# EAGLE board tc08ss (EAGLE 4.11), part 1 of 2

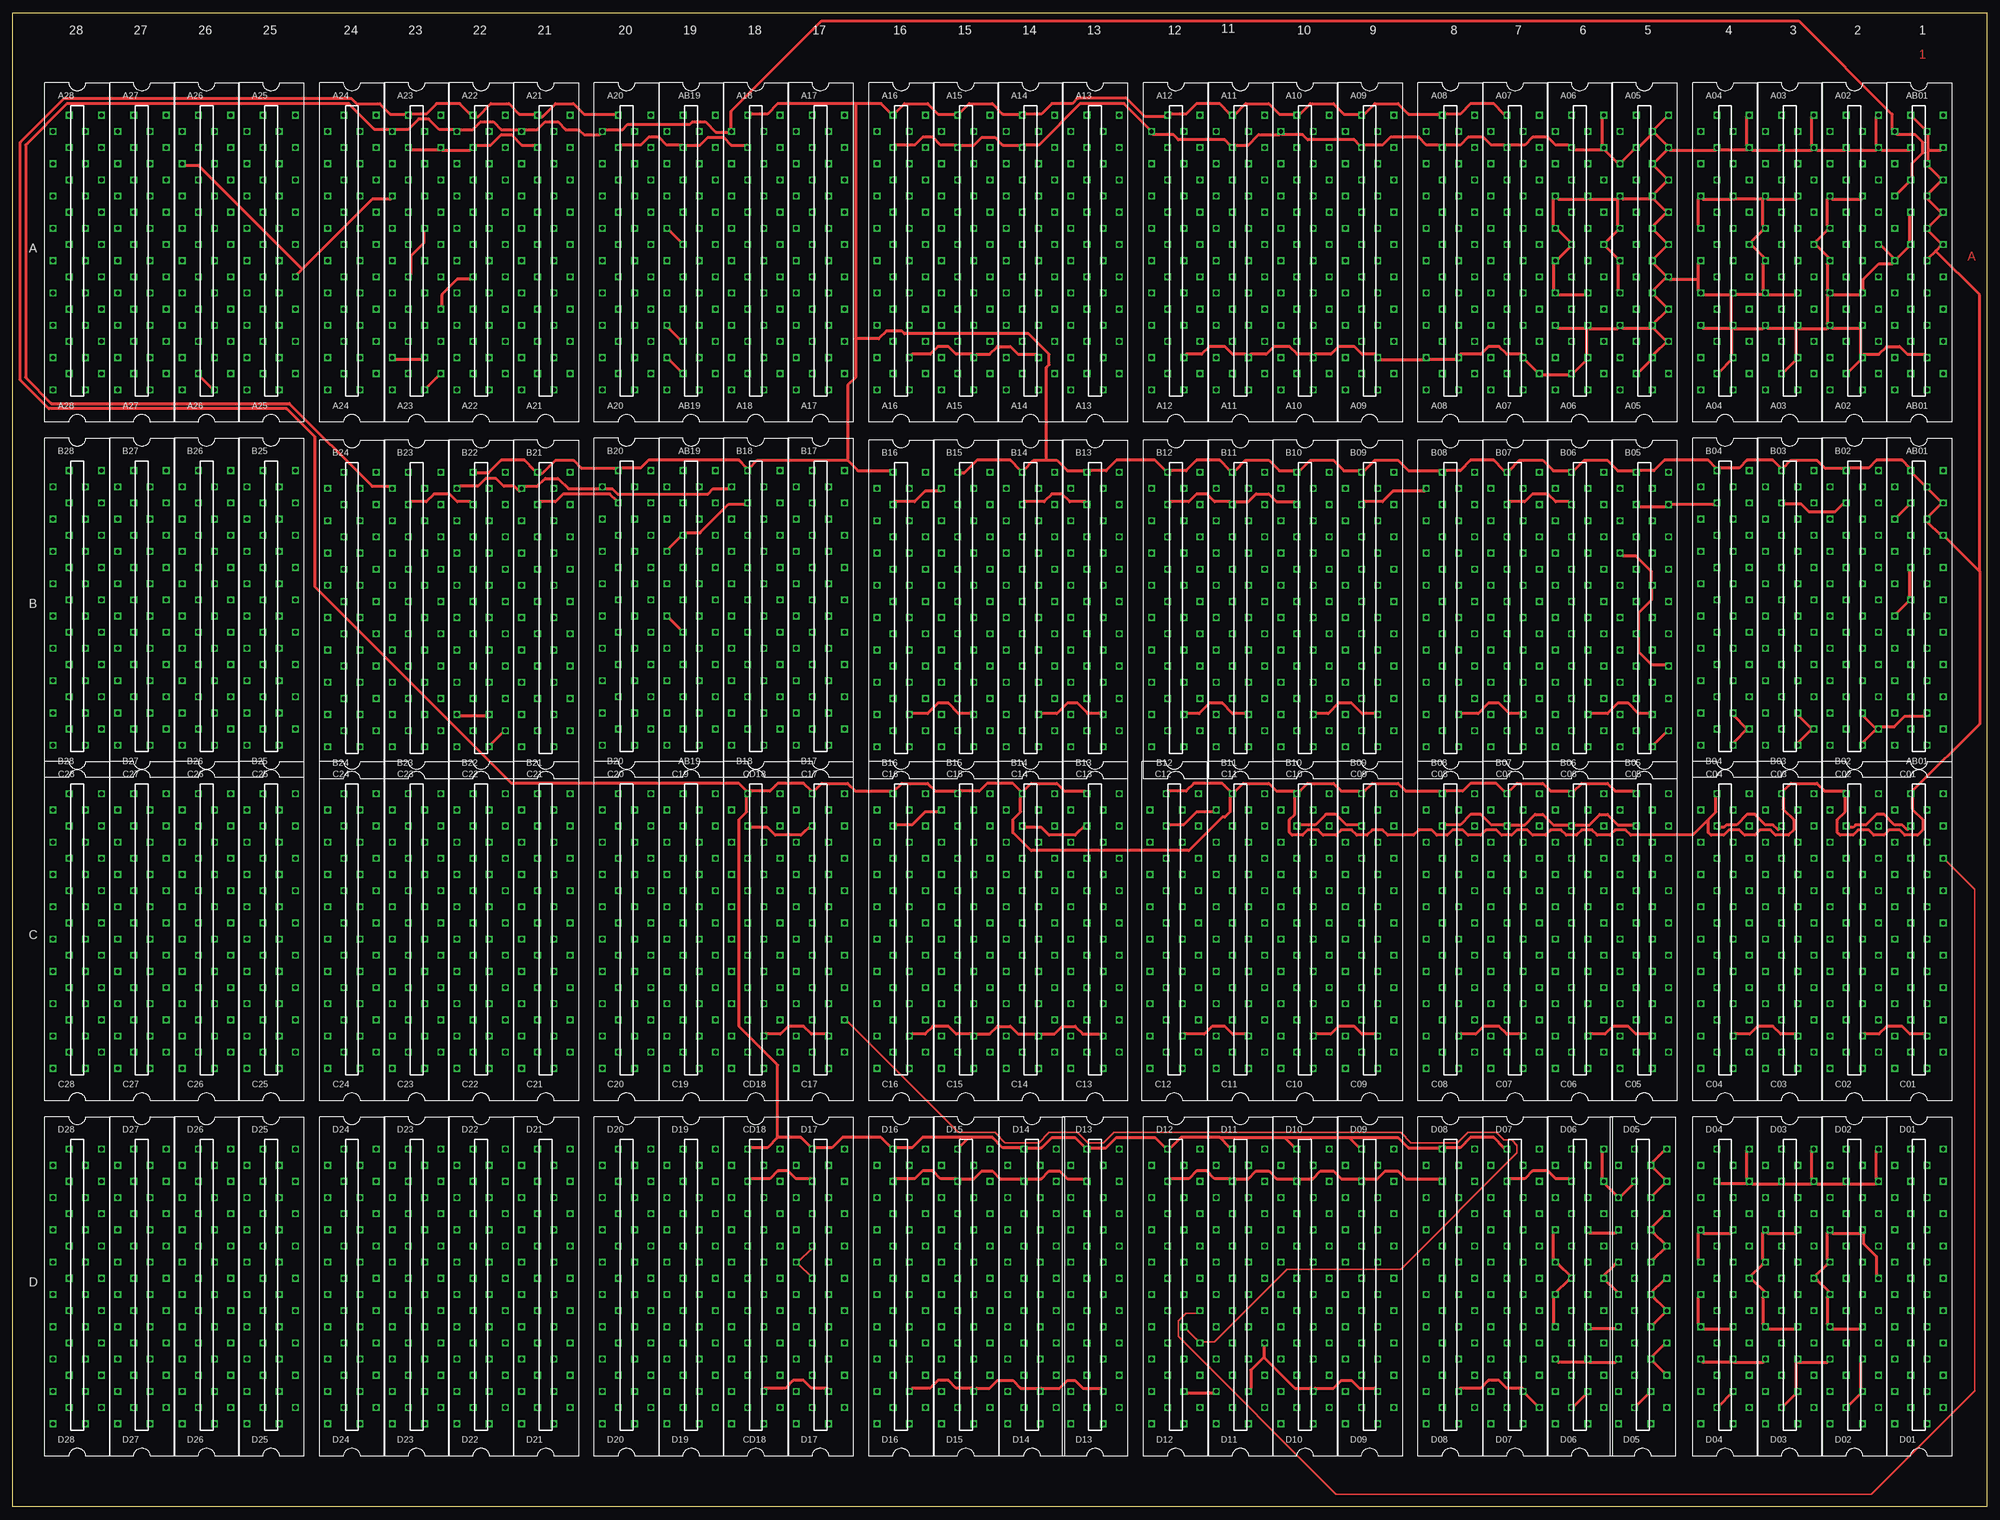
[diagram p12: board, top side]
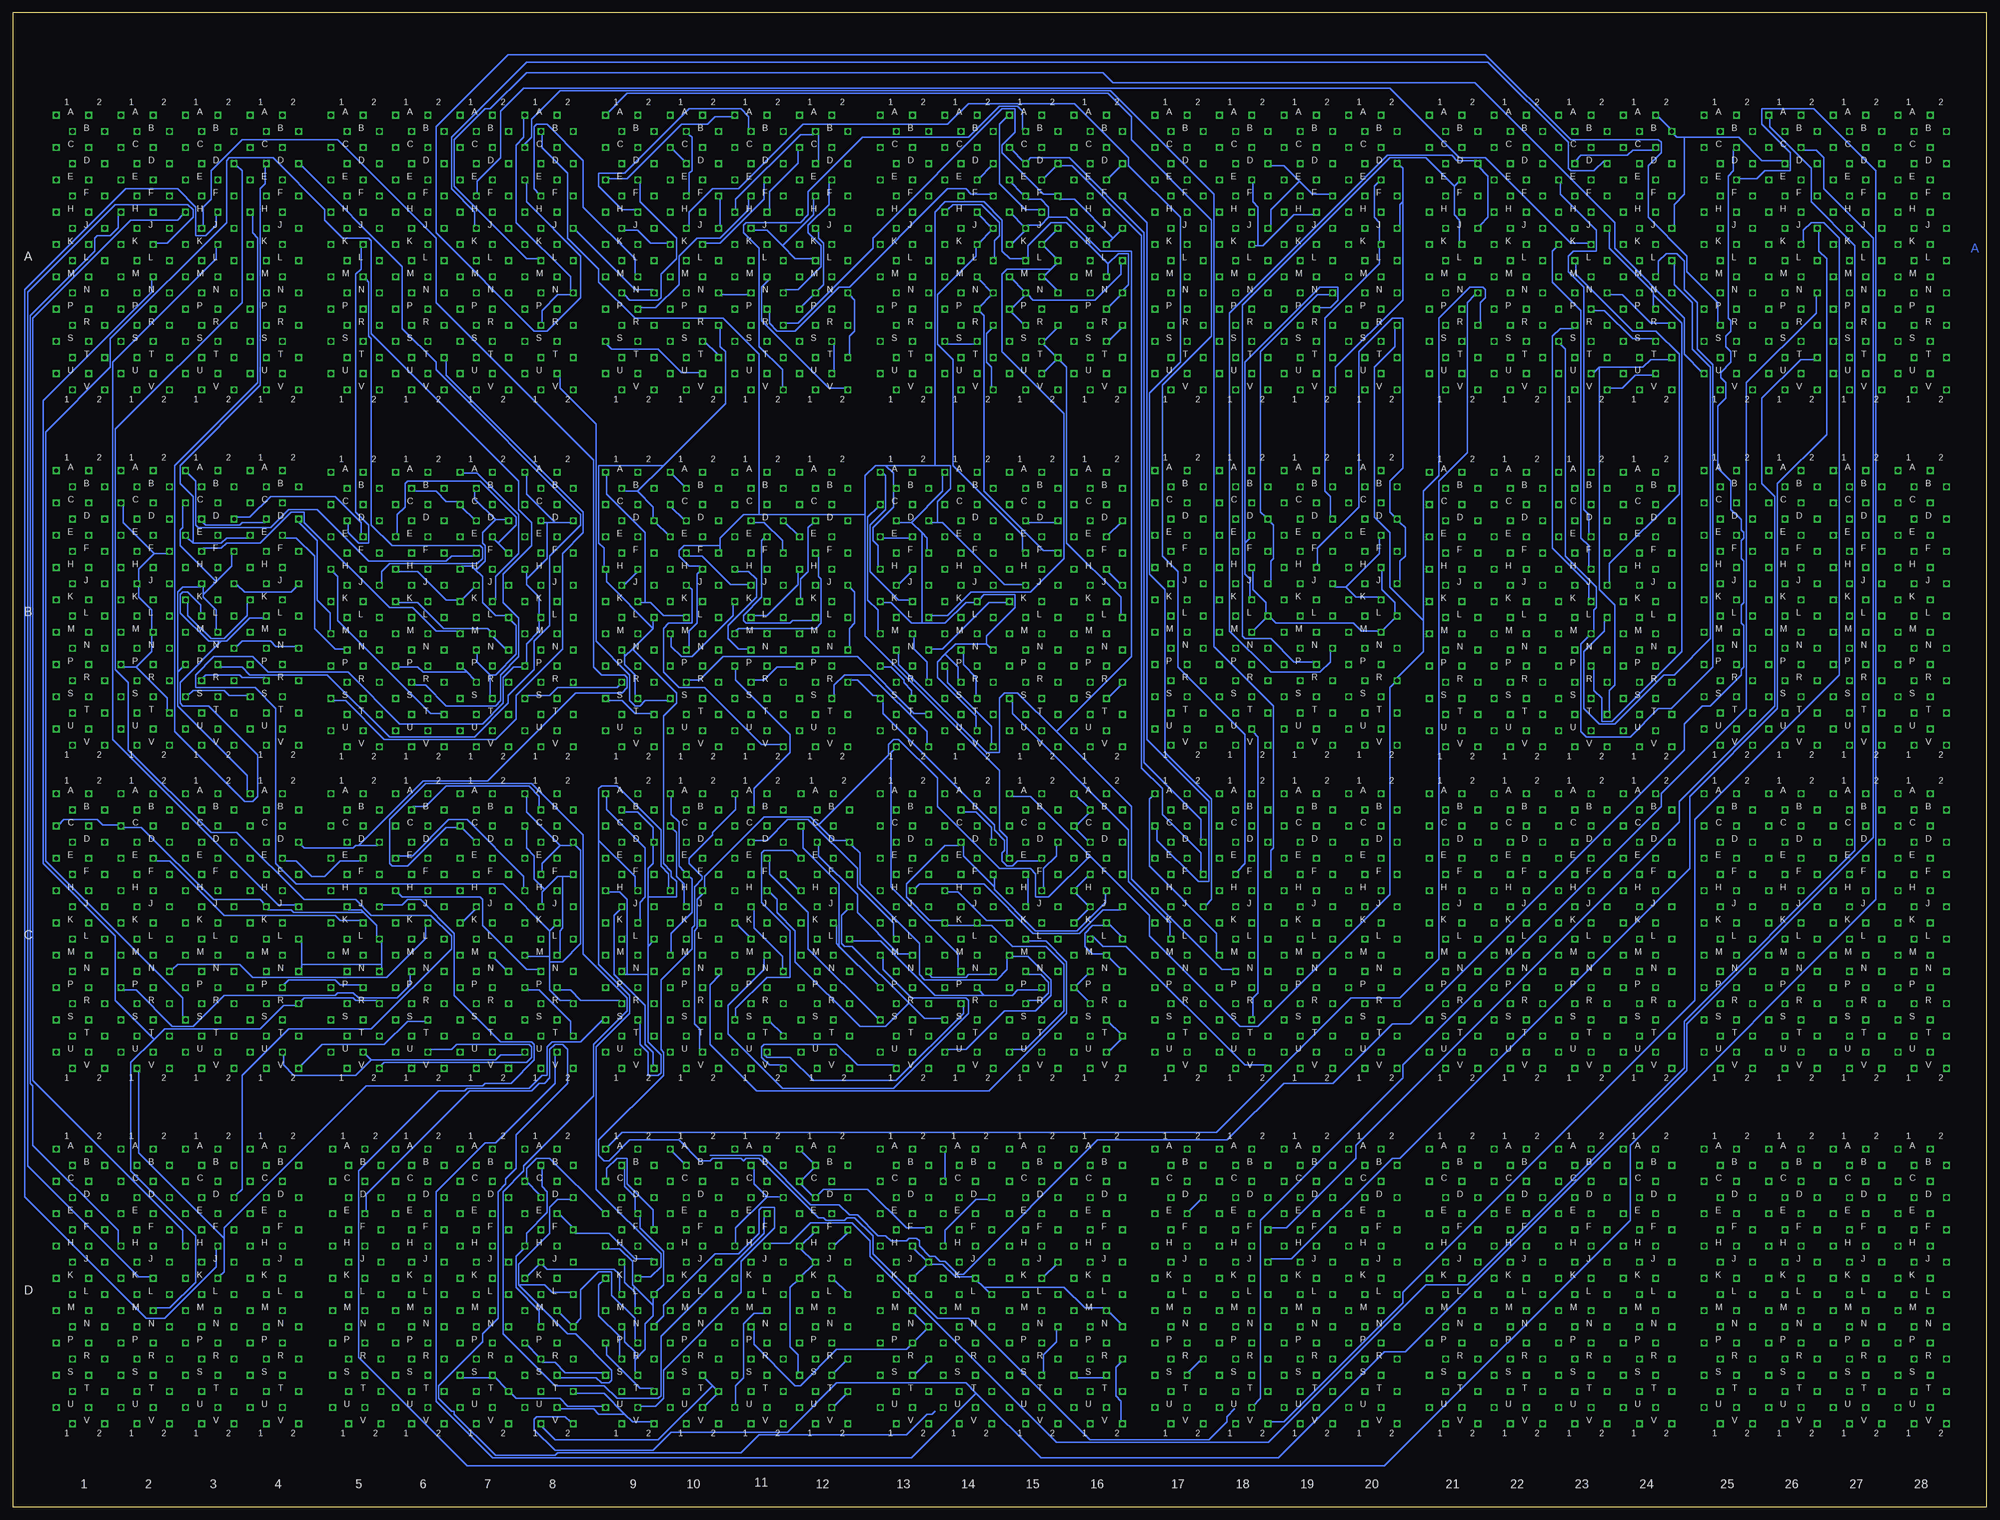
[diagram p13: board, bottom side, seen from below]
Size 387.97 x 293.68 mm. Coordinates in mm from the lower left corner, seen from the top.
Outline: 387.97,0 0,0 0,293.68 387.97,293.68 387.97,0
Copper layers (1*16): Top 0.035mm / dielectric 1.5mm / Bottom 0.035mm
Design rules "10mils": minimum track width 10mil, minimum drill 24mil, track to track 10mil, track to pad 10mil, pad to pad 10mil, via to via 10mil, smd to smd 10mil, copper to edge 40mil, drill to drill 10mil, minimum pad ring 10mil, minimum via ring 8mil, stop-mask expansion 0mil, vias tented up to drill 0mil, thermal gap 10mil
Net classes: 1 Power: width 0.635 mm, drill 0.381 mm, clearance 0.381 mm

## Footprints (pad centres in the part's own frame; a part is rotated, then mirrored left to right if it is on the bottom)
H807 = drill 0.813 square: A1 4.763,28.575; A2 -1.587,28.575; B1 1.587,25.4; B2 -4.763,25.4; C1 4.763,22.225; C2 -1.587,22.225; D1 1.587,19.05; D2 -4.763,19.05; E1 4.763,15.875; E2 -1.587,15.875; F1 1.587,12.7; F2 -4.763,12.7; H1 4.763,9.525; H2 -1.587,9.525; J1 1.587,6.35; J2 -4.763,6.35; K1 4.763,3.175; K2 -1.587,3.175; L1 1.587,0; L2 -4.763,0; M1 4.763,-3.175; M2 -1.587,-3.175; N1 1.587,-6.35; N2 -4.763,-6.35; P1 4.763,-9.525; P2 -1.587,-9.525; R1 1.587,-12.7; R2 -4.763,-12.7; S1 4.763,-15.875; S2 -1.587,-15.875; T1 1.587,-19.05; T2 -4.763,-19.05; U1 4.763,-22.225; U2 -1.587,-22.225; V1 1.587,-25.4; V2 -4.763,-25.4
H807-2 = drill 0.813 square: AA1 4.763,60.325; AA2 -1.587,60.325; AB1 1.587,57.15; AB2 -4.763,57.15; AC1 4.763,53.975; AC2 -1.587,53.975; AD1 1.587,50.8; AD2 -4.763,50.8; AE1 4.763,47.625; AE2 -1.587,47.625; AF1 1.587,44.45; AF2 -4.763,44.45; AH1 4.763,41.275; AH2 -1.587,41.275; AJ1 1.587,38.1; AJ2 -4.763,38.1; AK1 4.763,34.925; AK2 -1.587,34.925; AL1 1.587,31.75; AL2 -4.763,31.75; AM1 4.763,28.575; AM2 -1.587,28.575; AN1 1.587,25.4; AN2 -4.763,25.4; AP1 4.763,22.225; AP2 -1.587,22.225; AR1 1.587,19.05; AR2 -4.763,19.05; AS1 4.763,15.875; AS2 -1.587,15.875; AT1 1.587,12.7; AT2 -4.763,12.7; AU1 4.763,9.525; AU2 -1.587,9.525; AV1 1.587,6.35; AV2 -4.763,6.35; BA1 4.763,-9.525; BA2 -1.587,-9.525; BB1 1.587,-12.7; BB2 -4.763,-12.7; BC1 4.763,-15.875; BC2 -1.587,-15.875; BD1 1.587,-19.05; BD2 -4.763,-19.05; BE1 4.763,-22.225; BE2 -1.587,-22.225; BF1 1.587,-25.4; BF2 -4.763,-25.4; BH1 4.763,-28.575; BH2 -1.587,-28.575; BJ1 1.587,-31.75; BJ2 -4.763,-31.75; BK1 4.763,-34.925; BK2 -1.587,-34.925; BL1 1.587,-38.1; BL2 -4.763,-38.1; BM1 4.763,-41.275; BM2 -1.587,-41.275; BN1 1.587,-44.45; BN2 -4.763,-44.45; BP1 4.763,-47.625; BP2 -1.587,-47.625; BR1 1.587,-50.8; BR2 -4.763,-50.8; BS1 4.763,-53.975; BS2 -1.587,-53.975; BT1 1.587,-57.15; BT2 -4.763,-57.15; BU1 4.763,-60.325; BU2 -1.587,-60.325; BV1 1.587,-63.5; BV2 -4.763,-63.5

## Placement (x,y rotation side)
A02  M903  [H807]  361.94,244.94 0 top
A03  M903  [H807]  349.24,244.94 0 top
A04  M903  [H807]  336.54,244.94 0 top
A05  M903  [H807]  320.66,244.94 0 top
A06  M903  [H807]  307.96,244.94 0 top
A07  A07  [H807]  295.26,244.94 0 top
A08  M206X  [H807]  282.56,244.94 0 top
A09  [H807]  266.69,244.94 0 top
A10  [H807]  253.99,244.94 0 top
A11  A11  [H807]  241.29,244.94 0 top
A12  A12  [H807]  228.59,244.94 0 top
A13  H807  [H807]  212.71,244.94 0 top
A14  [H807]  200.01,244.94 0 top
A15  [H807]  187.31,244.94 0 top
A16  [H807]  174.61,244.94 0 top
A17  H807  [H807]  158.74,244.94 0 top
A18  [H807]  146.04,244.94 0 top
A20  [H807]  120.64,244.94 0 top
A21  [H807]  104.76,244.94 0 top
A22  [H807]  92.06,244.94 0 top
A23  [H807]  79.36,244.94 0 top
A24  W023  [H807]  66.66,244.94 0 top
A25  M916  [H807]  50.78,244.94 0 top
A26  M916  [H807]  38.09,244.94 0 top
A27  H807  [H807]  25.38,244.94 0 top
A28  H807  [H807]  12.68,244.94 0 top
AB01  [H807-2]  374.63,213.19 0 top
AB19  [H807-2]  133.34,213.19 0 top
B02  [H807]  361.94,175.09 0 top
B03  [H807]  349.24,175.09 0 top
B04  [H807]  336.54,175.09 0 top
B05  [H807]  320.66,174.78 0 top
B06  B06  [H807]  307.96,174.78 0 top
B07  B07  [H807]  295.26,174.78 0 top
B08  B08  [H807]  282.56,174.78 0 top
B09  M206X  [H807]  266.69,174.78 0 top
B10  B10  [H807]  253.99,174.78 0 top
B11  [H807]  241.29,174.78 0 top
B12  [H807]  228.59,174.78 0 top
B13  M206X  [H807]  212.71,174.78 0 top
B14  M206X  [H807]  200.01,174.78 0 top
B15  [H807]  187.31,174.78 0 top
B16  [H807]  174.61,174.78 0 top
B17  H807  [H807]  158.74,175.09 0 top
B18  [H807]  146.04,175.09 0 top
B20  [H807]  120.64,175.09 0 top
B21  [H807]  104.76,174.78 0 top
B22  [H807]  92.06,174.78 0 top
B23  [H807]  79.36,174.78 0 top
B24  H807  [H807]  66.66,174.78 0 top
B25  H807  [H807]  50.78,175.09 0 top
B26  H807  [H807]  38.09,175.09 0 top
B27  H807  [H807]  25.38,175.09 0 top
B28  H807  [H807]  12.68,175.09 0 top
C01  C01  [H807]  374.63,111.59 0 top
C02  [H807]  361.94,111.59 0 top
C03  [H807]  349.24,111.59 0 top
C04  C04  [H807]  336.54,111.59 0 top
C05  C05  [H807]  320.66,111.59 0 top
C06  C06  [H807]  307.96,111.59 0 top
C07  B07  [H807]  295.26,111.59 0 top
C08  C08  [H807]  282.56,111.59 0 top
C09  M206X  [H807]  266.69,111.59 0 top
C10  [H807]  253.99,111.59 0 top
C11  [H807]  241.29,111.59 0 top
C12  [H807]  228.27,111.59 0 top
C13  [H807]  212.71,111.59 0 top
C14  M206X  [H807]  200.01,111.59 0 top
C15  [H807]  187.31,111.59 0 top
C16  C16  [H807]  174.61,111.59 0 top
C17  C17  [H807]  158.74,111.59 0 top
C19  H807  [H807]  133.34,111.59 0 top
C20  H807  [H807]  120.64,111.59 0 top
C21  H807  [H807]  104.76,111.59 0 top
C22  H807  [H807]  92.06,111.59 0 top
C23  H807  [H807]  79.36,111.59 0 top
C24  H807  [H807]  66.66,111.59 0 top
C25  H807  [H807]  50.78,111.59 0 top
C26  H807  [H807]  38.09,111.59 0 top
C27  H807  [H807]  25.38,111.59 0 top
C28  H807  [H807]  12.68,111.59 0 top
CD18  [H807-2]  146.04,79.84 0 top
D01  H807  [H807]  374.63,41.74 0 top
D02  M903  [H807]  361.94,41.74 0 top
D03  M903  [H807]  349.24,41.74 0 top
D04  M903  [H807]  336.54,41.74 0 top
D05  M903  [H807]  320.34,41.74 0 top
D06  M903  [H807]  307.96,41.74 0 top
D07  D07  [H807]  295.26,41.74 0 top
D08  [H807]  282.56,41.74 0 top
D09  [H807]  266.69,41.74 0 top
D10  [H807]  253.99,41.74 0 top
D11  M206X  [H807]  241.29,41.74 0 top
D12  D12  [H807]  228.59,41.74 0 top
D13  D13  [H807]  212.71,41.74 0 top
D14  [H807]  200.33,41.74 0 top
D15  [H807]  187.31,41.74 0 top
D16  [H807]  174.61,41.74 0 top
D17  D17  [H807]  158.74,41.74 0 top
D19  H807  [H807]  133.34,41.74 0 top
D20  H807  [H807]  120.64,41.74 0 top
D21  H807  [H807]  104.76,41.74 0 top
D22  H807  [H807]  92.06,41.74 0 top
D23  H807  [H807]  79.36,41.74 0 top
D24  H807  [H807]  66.66,41.74 0 top
D25  H807  [H807]  50.78,41.74 0 top
D26  H807  [H807]  38.09,41.74 0 top
D27  H807  [H807]  25.38,41.74 0 top
D28  H807  [H807]  12.68,41.74 0 top

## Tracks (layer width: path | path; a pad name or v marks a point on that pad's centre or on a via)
0_TO_AC\
  Bottom 0.254: B06.T2 303.77,155.92 305.8,155.92 324.09,174.21 324.09,182.84 325.11,183.86 B05.H1
0_TO_DTB\
  Bottom 0.254: C09.K2 264.65,115.28 264.65,118.83 263.64,119.85 263.64,129.5 271.26,137.12 271.26,139.66 C09.A1 | 263.64,177.76 264.65,177.76 B09.K2 | 263.64,177.76 262.62,177.76 260.08,175.22 256.02,175.22 B10.L1 | 263.64,177.76 263.64,191.48 271.26,199.1 271.26,203.16 B09.A1
0_TO_EF
  Bottom 0.254: A11.E2 240.27,260.57 240.27,257.01 248.91,248.37 251.95,248.37 A10.K2
0_TO_EF\
  Bottom 0.254: A08.R1 283.96,232.63 283.96,235.17 280.91,238.21 278.37,238.21 A08.N2 278.37,239.23 278.37,241.77 289.04,252.44 289.04,267.68 287.51,269.2 287.51,273.27 A08.A1
0_TO_STA
  Bottom 0.254: A11.N1 243.32,238.21 248.91,238.21 A10.N2
0_TO_STA\
  Bottom 0.254: B07.K2 293.1,178.27 293.1,182.84 288.53,187.41 288.53,195.03 296.66,203.16 299.71,203.16 B07.A1
0_TO_STATE\
  Bottom 0.254: CD18.AV2 141.72,86.83 145.78,86.83 169.15,110.2 173.72,110.2 175.75,112.23 C16.L1
02\
  Bottom 0.254: A07.J1 297.17,251.93 297.17,254.47 301.74,259.04 301.74,269.2 287,283.93 98.03,283.93 82.28,268.19 82.28,263.11 81.77,262.6 77.2,262.6 75.17,264.63 A23.D2
04\
  Bottom 0.254: A23.K2 78.22,248.37 81.77,248.37 98.54,265.14 103.62,265.14 117.33,278.85 287.51,278.85 292.09,274.28 292.09,265.14 296.66,260.57 296.66,258.03 A07.F1
76
  Bottom 0.254: C06.S2 306.82,95.47 310.37,95.47 314.94,90.89 327.14,90.89 331.2,86.83 C04.V2
76\
  Bottom 0.254: D12.S2 226.55,26.38 224.01,28.92 D12.R2
77
  Bottom 0.254: C06.U2 305.8,89.88 301.74,89.88 300.72,90.89 286.5,90.89 285.99,90.39 285.99,88.35 287,87.34 314.94,87.34 315.45,86.83 C05.V2
77\
  Bottom 0.254: D12.T2 224.01,22.31 226.55,19.77 D12.U2
+3V@B12U1
  Bottom 0.254: 204.71,167.6 202.68,169.63 196.58,169.63 | 204.71,167.6 206.23,166.08 206.23,163.03 198.61,155.41 198.61,152.87 B14.U2 | 196.58,169.63 195.57,168.62 B14.N2 | 204.71,167.6 202.17,165.06 202.17,162.52 B14.R1 | 209.28,173.7 211.31,173.7 215.38,177.76 216.9,177.76 B13.K1 | 209.28,173.7 204.71,173.7 200.65,177.76 198.61,177.76 B14.K2 198.11,178.27 197.09,179.29 190.99,179.29 190.99,176.75 196.58,171.16 196.58,169.63 | 209.28,191.48 211.31,193.51 | 209.28,191.48 208.27,190.46 208.27,187.92 B13.F2 | 211.31,193.51 213.85,193.51 B13.D1 | 211.31,193.51 205.22,199.61 205.22,203.16 B14.A1 | 209.28,173.7 209.28,191.48
+3V@C08U1
  Bottom 0.254: 317.49,87.85 293.1,87.85 292.09,88.86 287.51,88.86 C08.U1 | 317.49,87.85 318.5,88.86 C05.U2 | 317.49,87.85 320.53,84.8 332.73,84.8 334.76,86.83 334.76,88.86 C04.U2 | C01.C1 378.95,134.07 377.94,135.09 371.33,135.09 370.32,134.07 367.27,134.07 C02.C1 366.25,133.57 362.7,133.57 348.47,119.34 339.33,119.34 338.31,118.33 C04.J1 337.81,117.31 333.23,117.31 332.73,116.8 319.01,116.8 | 331.2,106.64 331.2,111.21 C04.L2 | 331.2,106.64 331.2,105.63 C04.N2 | 315.45,106.64 315.45,111.21 C05.L2 316.47,112.23 316.47,114.26 319.01,116.8 | 315.45,106.64 315.45,105.63 C05.N2 | 319.01,116.8 319.52,117.31 322.06,117.31 C05.J1 | 315.45,106.64 331.2,106.64
+3V@C15U1
  Bottom 0.254: 195.06,121.88 195.06,123.91 C14.F2 | 195.06,121.88 195.06,121.37 186.93,113.25 178.8,113.25 173.21,118.83 173.21,120.87 C16.H2 | 195.06,121.88 201.15,127.98 201.15,130.01 C14.D1 202.17,130.01 204.71,130.01 212.33,122.39 212.33,119.85 207.76,115.28 205.22,115.28 C14.K1 204.2,114.26 198.61,114.26 C14.K2 198.11,114.26 195.57,114.26 191.5,110.2 184.9,110.2 181.34,106.64 181.34,97.5 188.96,89.88 191.5,89.88 C15.U1
+3V@D09U1
  Bottom 0.254: D09.U1 271.76,19.77 278.88,19.77 280.4,21.3 289.04,21.3 290.05,22.31 D07.T2 291.07,23.33 293.1,25.36 D07.S2 294.12,25.36 299.71,25.36 D07.S1
-15V
  Top 0.635: AB01.AF2 370.32,258.03 372.86,260.57 AB01.AE2 373.37,261.07 373.37,264.12 375.4,266.15 375.4,268.19 373.87,269.71 370.32,269.71 AB01.AB2 369.3,270.73 369.3,273.77 351.01,292.06 158.99,292.06 141.21,274.28 141.21,270.73 A18.B2 140.7,270.22 138.16,270.22 136.13,272.25 133.59,272.25 133.08,271.74 120.89,271.74 119.87,270.73 116.32,270.73 A20.B2 115.3,269.71 112.25,269.71 111.24,270.73 108.7,270.73 107.17,272.25 104.63,272.25 103.11,270.73 100.57,270.73 A21.B2 99.55,270.73 96,270.73 94.47,272.25 91.93,272.25 90.41,270.73 87.87,270.73 A22.B2 86.85,270.73 83.8,270.73 81.77,272.76 79.74,272.76 77.71,270.73 75.17,270.73 A23.B2 74.15,270.73 71.11,270.73 66.03,275.81 10.65,275.81 2.52,267.68 2.52,221.96 7.61,216.88 54.34,216.88 70.6,200.62 74.15,200.62 B23.B2 | B22.B2 87.87,200.62 91.42,200.62 92.95,202.15 94.98,202.15 96.5,200.62 98.54,200.62 99.55,199.61 B21.B2 100.57,200.62 103.11,200.62 104.63,202.15 107.17,202.15 109.2,200.11 115.3,200.11 B20.B2 116.32,200.11 117.84,200.11 118.86,199.1 136.64,199.1 137.65,200.11 140.7,200.11 B18.B2
B-BRK
  Top 0.254: D12.M1 233.16,38.06 230.62,38.06 229.09,36.54 229.09,33.49 260.08,2.5 365.24,2.5 385.56,22.82 385.56,121.37 379.97,126.96 C01.E1
B-BRK\
  Bottom 0.254: 363.71,165.06 357.62,158.97 357.62,156.43 B02.T2 | 363.71,165.06 366.25,165.06 B02.P1 | 363.71,165.06 360.67,168.11 360.67,171.67 B02.M2 360.67,172.17 360.67,176.24 363.21,178.78 363.21,180.81 B02.J1 363.21,181.83 363.21,184.37 360.16,187.41 | 360.16,187.41 357.62,187.41 B02.F2 | 360.16,187.41 366.25,193.51 366.25,197.07 B02.C1
BAC_00
  Bottom 0.254: B07.D1 297.17,194.02 299.71,196.56 B07.C1 300.21,197.57 302.75,197.57 304.79,199.61 309.36,199.61 B06.B1
BAC_01
  Bottom 0.254: 292.59,189.45 293.61,190.46 B07.E2 | 292.59,189.45 291.07,187.92 B07.F2 | 292.59,189.45 289.04,193 289.04,194.53 296.15,201.64 310.37,201.64 310.88,201.13 310.88,196.56 312.41,195.03 312.41,190.97 B06.E1
BAC_02
  Bottom 0.254: B07.J1 297.17,180.81 299.71,178.27 B07.K1 300.21,178.27 302.75,178.27 308.34,183.86 312.41,183.86 B06.H1
BAC_03
  Bottom 0.254: B07.N2 291.07,168.62 293.61,171.16 B07.M2 294.12,172.17 294.62,172.68 303.26,172.68 308.34,177.76 312.41,177.76 B06.K1
BAC_04
  Bottom 0.254: C07.N2 291.07,105.63 293.61,108.17 C07.M2
BAC_05
  Bottom 0.254: 298.69,164.05 299.71,165.06 B07.P1 | 298.69,164.05 297.17,162.52 B07.R1 | 298.69,164.05 307.32,164.05 308.34,165.06 312.41,165.06 B06.P1
BAC_06\
  Bottom 0.254: C03.S1 354.57,95.97 354.57,100.04 381.49,126.96 381.49,211.29 368.79,223.99 368.79,229.58 345.93,252.44 345.93,264.63 345.43,265.14 336.79,265.14 326.63,254.98 326.63,252.95 323.07,249.39 317.99,249.39 317.49,248.88 317.49,230.59 288.53,201.64 288.53,196.05 285.99,193.51 285.99,188.94 291.58,183.35 291.58,177.76 288.53,174.71 288.53,167.09 292.09,163.54 292.09,158.46 293.1,157.44 302.75,157.44 306.82,161.51 309.36,161.51 B06.R1
BAC_07
  Bottom 0.254: D11.E2 240.27,57.37 240.27,53.81 260.59,33.49 260.59,21.81 261.1,21.3 269.23,21.3 271.76,23.84 281.42,23.84 291.58,34 291.58,61.94 287.51,66 287.51,67.02 273.8,80.73 273.8,90.89 267.19,97.5 267.19,100.04 275.83,108.67 275.83,132.04 285.99,142.2 306.82,142.2 313.93,135.09 313.93,126.45 313.42,125.95 310.37,125.95 302.75,133.57 300.21,133.57 C07.C1 299.71,133.57 297.17,131.03 C07.D1
BAC_09
  Bottom 0.254: C07.J1 297.17,117.31 299.71,114.77 C07.K1
BLK_IN_SYNC
  Bottom 0.254: C13.S1 217.92,95.97 231.63,109.69 231.63,116.8 239.25,124.42 239.25,126.96 C11.E2
BMB_00
  Bottom 0.254: C08.B1 284.47,137.63 284.47,139.66 286.5,141.69 302.75,141.69 306.82,137.63 309.36,137.63 C06.B1
BMB_01
  Bottom 0.254: C08.H1 287.51,121.37 287.51,123.91 298.69,135.09 302.25,135.09 309.36,127.98 312.41,127.98 C06.E1
BMB_02
  Bottom 0.254: C08.N1 284.47,105.63 287,105.63 295.64,114.26 295.64,119.34 296.15,119.85 311.39,119.85 312.41,120.87 C06.H1
BMB_05\
  Bottom 0.254: C06.N1 309.87,104.61 309.87,102.58 312.41,100.04 320.03,100.04 321.04,101.05 324.09,101.05 324.6,100.55 346.44,100.55 352.54,94.45 356.6,94.45 363.71,101.56 366.25,101.56 C02.P1
BMB_11\
  Bottom 0.254: C06.K2 306.82,114.26 306.82,111.72 314.44,104.1 340.85,104.1 343.39,106.64 355.59,106.64 356.6,105.63 C02.N2
BMB_TO_DTB
  Bottom 0.254: 282.94,193.51 283.96,193.51 B08.D1 | 282.94,193.51 281.42,193.51 | 281.42,193.51 278.37,193.51 B08.D2 | 281.42,193.51 287,199.1 287,203.16 B08.A1 | 287,182.33 287,183.86 B08.H1 | 287,182.33 287,181.32 284.47,178.78 284.47,175.22 B08.L1 284.47,174.21 284.47,172.17 287,169.63 287,165.57 B08.P1 287.51,165.06 289.55,165.06 291.58,163.03 291.58,157.95 295.64,153.89 311.9,153.89 322.06,164.05 337.81,164.05 340.85,167.09 348.47,167.09 352.03,163.54 352.03,161 340.35,161 336.28,156.93 336.28,126.45 332.22,122.39 291.58,122.39 282.43,113.25 | 282.94,193.51 282.94,186.4 287,182.33 | 282.43,113.25 282.43,108.17 | 282.43,108.17 282.43,107.15 | 282.43,107.15 282.43,101.56 280.4,99.53 278.37,99.53 C08.R2 | 282.43,113.25 281.42,114.26 C08.K2 | 282.43,108.17 287,108.17 C08.M1 | 280.4,130.01 278.37,130.01 C08.D2 277.35,130.01 276.34,128.99 276.34,110.71 279.89,107.15 282.43,107.15 | 280.4,130.01 283.96,126.45 283.96,124.93 C08.F1 | 280.4,130.01 287,136.61 287,139.66 C08.A1
C00
  Bottom 0.254: B12.R2 223.51,162.52 221.98,162.52 218.93,159.47 217.92,159.47 B13.S1 216.9,158.46 216.9,155.92 195.06,134.07 195.06,133.06 193.03,131.03 193.03,128.99 193.53,128.49 193.53,126.96 192.52,125.95 191.5,125.95 190.49,126.96 185.91,126.96 C15.E2
C00\
  Bottom 0.254: B13.S2 211.31,159.47 211.31,160.49 212.84,162.01 212.84,162.52 215.38,165.06 216.9,165.06 B13.P1
C01
  Bottom 0.254: B11.V2 236.71,149.82 240.78,149.82 251.95,161 257.03,161 260.08,164.05 260.08,172.68 259.06,173.7 254.49,173.7 254.49,180.3 255,180.81 B10.J1
C01\
  Bottom 0.254: B13.R2 208.27,162.52 208.27,166.08 210.81,168.62 210.81,171.16 B13.M2
CK01
  Bottom 0.254: C16.R1 176.77,99.53 178.8,101.56 C16.P1 178.8,102.58 176.77,104.61 C16.N1 | B14.V2 195.57,149.82 195.57,153.38 204.2,162.01 204.2,165.06 B14.P1
CK01\
  Bottom 0.254: C16.U2 172.71,89.37 170.17,91.91 C16.T2 170.17,92.93 172.71,95.47 C16.S2
COMP+SH
  Bottom 0.254: C15.K1 192.52,115.28 196.58,115.28 202.17,120.87 204.2,120.87 C14.H1 | C14.D2 195.57,131.03 195.57,133.57 198.61,136.61 201.15,136.61 C14.B1
DTB_01
  Bottom 0.254: 272.78,131.03 272.78,141.19 272.27,141.69 269.23,141.69 260.59,133.06 260.59,125.95 259.06,124.42 259.06,121.37 C10.H1 | 272.78,131.03 265.67,123.91 265.67,121.37 C09.H2 | 272.78,131.03 272.78,106.64 266.69,100.55 266.69,96.99 273.29,90.39 273.29,62.45 260.59,49.75 260.59,47.21 262.62,45.17 264.65,45.17 D09.K2
DTB_02
  Bottom 0.254: 250.94,69.05 240.78,69.05 231.12,59.4 225.54,59.4 223.51,57.37 221.98,57.37 217.92,53.3 216.39,53.3 215.38,52.29 212.33,52.29 211.82,52.79 210.3,52.79 209.79,52.29 209.79,51.27 207.76,49.24 206.74,49.24 205.73,48.22 204.71,48.22 202.17,45.68 201.15,45.68 174.74,72.1 149.34,72.1 138.16,83.27 128.51,83.27 116.83,94.96 113.27,94.96 59.42,148.81 59.42,153.89 55.87,157.44 54.34,157.44 48.24,163.54 48.24,164.55 47.74,165.06 47.74,173.19 48.24,173.7 48.24,177.25 47.74,177.76 47.74,185.89 48.24,186.4 48.24,189.95 47.74,190.46 47.74,191.48 48.24,191.99 48.24,194.02 50.28,196.05 50.28,201.64 52.82,204.18 52.82,216.37 51.29,217.89 51.29,220.94 52.31,221.96 52.31,222.97 50.28,225.01 50.28,227.04 51.29,228.05 51.29,230.09 50.28,231.1 50.28,233.13 50.78,233.64 50.78,261.58 49.77,262.6 49.77,266.66 A25.C2
DTB_04
  Bottom 0.254: A25.E2 48.75,261.07 45.2,261.07 43.67,262.6 38.59,262.6 38.59,266.15 44.18,271.74 44.18,274.79 34.02,274.79 21.83,262.6 21.83,119.34 70.09,71.08 70.09,56.35 118.35,8.09 298.69,8.09 320.03,29.43 320.03,66 304.28,81.75 299.2,81.75 298.69,82.26 286.5,82.26 283.96,84.8 282.94,84.8 282.94,90.39 281.93,91.4 276.34,91.4 271.76,95.97 C09.S1
DTB_05
  Bottom 0.254: C09.V2 262.11,86.83 262.11,89.37 263.64,90.89 263.64,98.51 269.73,104.61 269.73,116.29 268.72,117.31 C09.J1
DTB_10
  Bottom 0.254: B09.T2 262.11,155.92 265.67,155.92 268.21,158.46 271.26,158.46 B09.S1
DTB_11
  Bottom 0.254: B09.J1 267.7,181.32 265.16,183.86 B09.H2
EA_01\
  Bottom 0.254: A06.T2 302.75,225.51 302.75,222.47 275.83,195.54 275.83,191.48 279.89,187.41 279.89,168.62 289.04,159.47 289.04,154.9 293.1,150.84 314.94,150.84 322.56,158.46 325.11,158.46 B05.S1
EF
  Bottom 0.254: 236.71,247.87 239.76,250.91 242.3,250.91 A11.J1 | 236.71,247.87 234.17,245.33 230.62,245.33 A12.L1 | 236.71,247.87 230.62,253.96 230.62,257.01 A12.F1
END
  Bottom 0.254: A25.R1 52.82,232.63 52.82,236.69 58.91,242.79 58.91,245.83 66.53,253.45 66.53,263.61 63.99,266.15 63.99,268.19 64.5,268.69 81.77,268.69 98.54,285.46 290.56,285.46 304.79,271.23 304.79,250.41 285.48,231.1 282.94,231.1 276.34,237.71 276.34,245.83 287,256.5 287,260.57 A08.E1
END\
  Bottom 0.254: A09.M2 265.67,242.28 265.67,245.33 275.83,255.49 275.83,264.63 282.94,271.74 284.97,271.74 285.48,271.23 285.48,259.04 284.47,258.03 A08.F1
FR_01\
  Bottom 0.254: B05.E2 319.52,190.97 319.52,193.51 324.6,198.59 337.3,198.59 341.36,194.53 343.9,194.53 B03.D2
GND
  Top 0.635: B05.C2 319.52,196.56 325.11,196.56 B05.C1 325.61,197.07 334.76,197.07 B04.C2 | B07.C2 294.12,197.57 297.17,197.57 298.69,199.1 301.74,199.1 303.26,197.57 305.8,197.57 B06.C2 | B05.F2 316.47,186.91 319.01,186.91 322.06,183.86 322.06,181.32 B05.J1 322.06,180.81 322.06,178.27 319.52,175.73 319.52,172.17 B05.M2 319.52,171.16 319.52,168.11 322.06,165.57 325.11,165.57 B05.P1 | AB01.BL2 370.32,175.73 372.86,178.27 AB01.BK2 372.86,178.78 372.86,184.37 AB01.BH2 | AB01.BD2 370.32,194.53 372.86,197.07 AB01.BC2 | B03.C2 347.97,197.07 351.52,197.07 353.05,195.54 358.12,195.54 360.16,197.57 B02.C2 | B06.T1 309.87,155.92 313.42,155.92 315.45,157.95 317.49,157.95 319.52,155.92 322.06,155.92 B05.T1 | B05.V1 322.56,149.82 325.11,152.36 B05.U1 | B08.T1 284.47,155.92 288.02,155.92 290.05,157.95 292.09,157.95 294.12,155.92 296.66,155.92 B07.T1 | 353.55,152.87 351.01,150.33 B03.V1 | 353.55,152.87 B03.U1 353.55,152.87 | 353.55,152.87 351.01,155.41 B03.T1 | 340.85,152.87 338.31,150.33 B04.V1 | 340.85,152.87 B04.U1 340.85,152.87 | 340.85,152.87 338.31,155.41 B04.T1 | C04.C2 335.26,133.57 336.28,133.57 336.79,134.07 338.82,134.07 340.85,136.11 342.38,136.11 344.41,134.07 345.93,134.07 346.95,133.06 347.46,133.57 C03.C2 | 366.25,152.87 363.71,150.33 B02.V1 | 366.25,152.87 B02.U1 | 366.25,152.87 363.71,155.41 B02.T1 | 366.25,152.87 B02.U1 | AB01.BT1 375.91,155.41 371.84,155.41 369.81,153.38 367.27,153.38 B02.U1 | C02.C2 360.67,133.57 361.68,133.57 362.19,134.07 364.22,134.07 366.25,136.11 367.78,136.11 369.81,134.07 371.33,134.07 372.35,133.06 372.86,133.57 C01.C2 | C08.C2 281.42,134.07 284.47,134.07 286.5,136.11 288.53,136.11 290.56,134.07 293.1,134.07 C07.C2 294.12,134.07 297.17,134.07 299.2,136.11 300.72,136.11 302.75,134.07 305.8,134.07 C06.C2 306.82,134.07 309.87,134.07 311.9,136.11 313.42,136.11 315.45,134.07 318.5,134.07 C05.C2
  Top 0.635: C10.C2 252.97,134.07 256.02,134.07 258.05,136.11 260.08,136.11 262.11,134.07 264.65,134.07 C09.C2 | B10.T1 256.02,155.92 258.56,155.92 260.59,157.95 263.13,157.95 265.16,155.92 267.7,155.92 B09.T1 | B12.T1 230.62,155.92 233.16,155.92 235.19,157.95 237.73,157.95 239.76,155.92 242.3,155.92 B11.T1 | B14.T1 202.17,155.92 205.22,155.92 207.25,157.95 209.28,157.95 211.31,155.92 213.85,155.92 B13.T1 | B16.T1 176.77,155.92 179.82,155.92 181.85,157.95 183.88,157.95 185.91,155.92 188.45,155.92 B15.T1 | C12.C2 227.06,134.07 230.11,134.07 232.65,136.61 236.21,136.61 C11.B2 | C14.C2 198.61,133.57 202.17,133.57 203.69,132.04 208.77,132.04 210.81,134.07 C13.C2 | B14.C2 198.61,197.57 202.68,197.57 204.2,199.1 206.23,199.1 207.76,197.57 210.81,197.57 B13.C2 | B16.C2 173.21,197.57 177.28,197.57 179.31,199.61 182.36,199.61 B15.B2 | A16.T1 176.77,226.53 180.33,226.53 181.85,228.05 183.88,228.05 185.41,226.53 188.45,226.53 A15.T1 189.47,226.53 192.01,226.53 193.53,228.05 196.07,228.05 197.6,226.53 201.15,226.53 A14.T1 | B12.C2 227.57,197.57 231.12,197.57 232.65,199.1 234.68,199.1 236.21,197.57 239.25,197.57 B11.C2 240.27,197.57 242.81,197.57 244.33,199.1 246.87,199.1 248.4,197.57 251.95,197.57 B10.C2 | B09.C2 265.67,197.57 269.23,197.57 271.26,199.61 277.35,199.61 B08.B2 | 56.88,243.29 70.6,257.01 74.15,257.01 A23.F2 | 56.88,243.29 55.87,242.28 A25.M1 | 56.88,243.29 36.56,263.61 33.51,263.61 A26.D2 | A26.V1 39.1,219.93 36.56,222.47 A26.U2 | A23.C2 78.22,266.66 83.8,266.66 A23.C1 84.31,266.66 89.9,266.66 A22.C2 90.92,267.68 93.97,267.68 96,269.71 98.03,269.71 100.06,267.68 102.6,267.68 A21.C2
  Top 0.635: A23.M2 78.22,242.28 78.22,245.83 80.76,248.37 80.76,250.91 A23.J1 | A23.P1 84.31,235.67 84.31,238.21 87.36,241.26 89.9,241.26 A22.M2 | A23.T2 75.17,225.51 80.76,225.51 A23.T1 | A23.V1 81.27,219.93 83.8,222.47 A23.U1 | A20.C2 119.36,267.68 123.43,267.68 124.95,269.2 126.98,269.2 128.51,267.68 131.56,267.68 AB19.AC2 132.07,267.68 135.11,267.68 136.64,269.2 139.69,269.2 141.21,267.68 144.26,267.68 A18.C2 | AB19.AJ2 129.02,250.91 131.56,248.37 AB19.AK2 | AB19.AU2 131.56,222.97 129.02,225.51 AB19.AT2 | AB19.AR2 129.02,231.61 131.56,229.07 AB19.AS2 | AB19.BF2 129.02,188.43 131.56,190.97 AB19.BE2 132.07,191.48 135.11,191.48 140.7,197.07 144.26,197.07 B18.C2 | AB19.BL2 129.02,174.71 131.56,172.17 AB19.BM2 | B22.T2 87.87,155.41 93.46,155.41 B22.T1 | B22.V1 93.97,149.82 96.5,152.36 B22.U1 | B21.C2 103.62,197.57 106.67,197.57 108.19,199.1 117.33,199.1 118.86,197.57 B20.C2 | B23.C2 78.22,197.57 81.27,197.57 82.79,199.1 85.84,199.1 87.36,197.57 89.9,197.57 B22.C2 | C16.T1 176.77,92.93 179.31,92.93 180.83,94.45 183.88,94.45 185.41,92.93 188.45,92.93 C15.T1 189.47,92.93 192.01,92.93 193.53,94.45 196.07,94.45 197.6,92.93 201.15,92.93 C14.T1 202.17,92.93 204.71,92.93 206.23,94.45 208.77,94.45 210.3,92.93 213.85,92.93 C13.T1 | CD18.AT1 147.81,92.93 150.86,92.93 152.39,94.45 155.43,94.45 156.96,92.93 160.01,92.93 C17.T1 | C12.T1 230.11,92.93 234.17,92.93 235.7,94.45 238.24,94.45 239.76,92.93 242.3,92.93 C11.T1 | C10.T1 256.02,92.93 259.06,92.93 260.59,94.45 263.64,94.45 265.16,92.93 267.7,92.93 C09.T1 | CD18.AC2 144.77,133.57 148.32,133.57 149.85,132.04 154.93,132.04 156.96,134.07 C17.C2
  Top 0.635: C16.C2 173.21,134.07 176.77,134.07 179.31,136.61 182.36,136.61 C15.B2 | C02.T1 363.71,92.93 366.76,92.93 368.29,94.45 371.33,94.45 372.86,92.93 375.91,92.93 C01.T1 | C04.T1 338.31,92.93 341.36,92.93 342.88,94.45 345.93,94.45 347.46,92.93 350.5,92.93 C03.T1 | C06.T1 309.87,92.93 312.91,92.93 314.44,94.45 317.49,94.45 319.01,92.93 322.06,92.93 C05.T1 | C08.T1 284.47,92.93 287.51,92.93 289.04,94.45 292.09,94.45 293.61,92.93 296.66,92.93 C07.T1 | D06.A1 312.41,70.07 312.41,64.48 D06.C1 312.91,63.46 314.94,61.43 D05.D2 315.96,60.92 318.5,63.46 D05.C2 | D05.D1 322.56,61.43 324.6,63.46 D05.C1 324.6,64.48 322.56,66.51 D05.B1 322.06,67.53 324.6,70.07 D05.A1 | D07.C2 294.12,64.48 297.17,64.48 298.69,66 301.74,66 303.26,64.48 305.8,64.48 D06.C2 | D04.C2 335.26,63.46 340.85,63.46 D04.C1 | D04.A1 340.85,70.07 340.85,64.48 D04.C1 | D04.C1 341.87,63.46 347.46,63.46 D03.C2 347.97,63.46 353.55,63.46 D03.C1 | D03.A1 353.55,70.07 353.55,64.48 D03.C1 | D03.C1 354.57,63.46 360.16,63.46 D02.C2 360.67,63.46 366.25,63.46 D02.C1 366.25,64.48 366.25,70.07 D02.A1 | D05.J1 322.56,48.73 324.6,50.76 D05.H1 324.6,51.78 322.56,53.81 D05.F1 322.06,54.83 324.6,57.37 D05.E1 | D05.N1 322.56,36.03 324.6,38.06 D05.M1 324.6,39.08 322.56,41.11 D05.L1 322.06,42.13 324.6,44.67 D05.K1 | D05.S1 324.6,26.38 322.56,28.41 D05.R1 322.06,29.43 324.6,31.97 D05.P1 | D05.U2 319.01,19.77 321.55,22.31 D05.T1 | D02.N1 363.21,35.01 357.62,35.01 D02.N2 356.6,36.03 356.6,41.11 D02.L2 357.11,42.13 354.57,44.67 D03.K1 354.06,45.17 356.6,47.71 D02.J2 356.6,48.73 356.6,53.81 D02.F2 357.62,53.81 363.21,53.81 D02.F1 363.71,53.81 363.71,51.78 366.25,49.24 366.25,45.17 D02.K1
  Top 0.635: D03.U2 347.97,19.77 350.5,22.31 D03.T1 350.5,23.33 350.5,28.41 D03.R1 351.01,28.41 356.6,28.41 D02.R2 | D02.U2 360.67,19.77 363.21,22.31 D02.T1 363.21,23.33 363.21,28.41 D02.R1 | D03.N1 350.5,35.01 344.92,35.01 D03.N2 343.9,36.03 343.9,41.11 D03.L2 344.41,42.13 341.87,44.67 D04.K1 341.36,45.17 343.9,47.71 D03.J2 343.9,48.73 343.9,53.81 D03.F2 344.92,53.81 350.5,53.81 D03.F1 | D04.J2 331.2,48.73 331.2,53.81 D04.F2 332.22,53.81 337.81,53.81 D04.F1 | D04.R2 332.22,28.41 337.81,28.41 D04.R1 338.31,28.41 343.9,28.41 D03.R2 | D04.U2 335.26,19.77 337.81,22.31 D04.T1 | D04.L2 331.2,41.11 331.2,36.03 D04.N2 332.22,35.01 337.81,35.01 D04.N1 | D06.R2 303.77,28.41 309.36,28.41 D06.R1 309.87,28.41 314.94,28.41 D05.R2 | D06.U2 306.82,19.77 309.36,22.31 D06.T1 | D08.T1 284.47,23.33 288.53,23.33 290.05,24.85 292.09,24.85 293.61,23.33 296.66,23.33 D07.T1 297.17,22.31 299.71,19.77 D07.U1 | D05.L2 315.45,42.13 312.91,44.67 D06.K1 312.41,45.17 314.94,47.71 D05.J2 | D06.N1 309.87,35.01 314.94,35.01 D05.N2 | D06.F1 309.87,53.81 314.94,53.81 D05.F2 | D06.N2 302.75,36.03 302.75,41.11 D06.L2 303.26,42.13 305.8,44.67 D06.K2 306.31,45.17 303.77,47.71 D06.J2 302.75,48.73 302.75,53.81 D06.F2 | 245.86,29.43 243.32,26.89 243.32,23.33 D11.T1 | 245.86,29.43 245.86,31.97 D11.P1 | 245.86,29.43 251.95,23.33 255,23.33 D10.T1 256.02,23.33 259.57,23.33 261.1,24.85 263.13,24.85 264.65,23.33 267.7,23.33 D09.T1 | D16.C2 173.21,64.48 177.28,64.48 178.8,66 180.83,66 182.36,64.48 185.41,64.48 D15.C2 185.91,64.48 188.96,64.48 190.49,66 192.52,66 194.04,64.48 198.11,64.48 D14.C2 199.12,64.48 202.17,64.48 203.69,66 205.73,66 207.25,64.48 210.81,64.48 D13.C2
  Top 0.635: CD18.BC2 144.77,64.48 148.83,64.48 150.35,66 152.39,66 153.91,64.48 156.96,64.48 D17.C2 | D12.C2 227.57,64.48 231.12,64.48 232.65,66 234.68,66 236.21,64.48 239.25,64.48 D11.C2 240.27,64.48 242.81,64.48 244.33,66 246.87,66 248.4,64.48 251.95,64.48 D10.C2 252.97,64.48 255.51,64.48 257.03,66 259.57,66 261.1,64.48 264.65,64.48 D09.C2 265.67,64.48 268.21,64.48 269.73,66 272.27,66 273.8,64.48 280.4,64.48 D08.C2 | D16.T1 176.77,23.33 180.33,23.33 181.85,24.85 183.88,24.85 185.41,23.33 188.45,23.33 D15.T1 189.47,23.33 192.01,23.33 193.53,24.85 196.58,24.85 198.11,23.33 201.66,23.33 D14.T1 202.17,23.33 205.73,23.33 207.25,24.85 208.77,24.85 210.3,23.33 213.85,23.33 D13.T1 | D12.T1 230.62,22.31 236.21,22.31 D11.T2 | CD18.BT1 147.81,23.33 151.88,23.33 153.4,24.85 155.43,24.85 156.96,23.33 160.01,23.33 D17.T1 | 331.2,241.26 331.2,244.31 A04.L2 | 331.2,241.26 331.2,239.23 A04.N2 332.22,238.21 337.81,238.21 | 337.81,238.21 A04.N1 | A04.U2 335.26,222.97 337.81,225.51 A04.T1 337.81,226.53 337.81,231.61 | 337.81,231.61 332.22,231.61 A04.R2 | 337.81,231.61 A04.R1 | A04.R1 338.31,231.61 343.9,231.61 A03.R2 344.92,231.61 350.5,231.61 | 337.81,231.61 A04.R1 | 337.81,238.21 337.81,232.63 A04.R1 | 337.81,238.21 A04.N1 | A04.J2 331.2,251.93 331.2,257.01 A04.F2 332.22,257.01 337.81,257.01 A04.F1 338.31,257.01 343.9,257.01 | A03.N2 343.9,239.23 343.9,244.31 A03.L2 344.41,245.33 341.87,247.87 A04.K1 341.36,248.37 343.9,250.91 A03.J2 343.9,251.93 343.9,257.01 | A03.N1 350.5,238.21 344.92,238.21 A03.N2 | 343.9,257.01 A03.F2 | A03.F1 350.5,257.01 344.92,257.01 A03.F2
  Top 0.635: 343.9,257.01 A03.F2 | A04.N1 338.31,238.21 343.9,238.21 A03.N2 | A03.U2 347.97,222.97 350.5,225.51 A03.T1 350.5,226.53 350.5,231.61 | 350.5,231.61 A03.R1 | A02.R2 356.6,231.61 351.01,231.61 A03.R1 | A02.U2 360.67,222.97 363.21,225.51 A02.T1 | 363.21,231.61 363.21,226.53 A02.T1 | 363.21,231.61 A02.R1 363.21,231.61 | AB01.AT1 375.91,226.53 372.35,226.53 370.82,228.05 368.29,228.05 366.76,226.53 363.71,226.53 A02.T1 | 363.21,231.61 357.62,231.61 A02.R2 | A02.K1 367.27,247.87 369.81,245.33 AB01.AL2 | AB01.AL2 370.32,245.33 372.86,247.87 AB01.AK2 372.86,248.37 372.86,253.96 AB01.AH2 | A02.N2 356.6,239.23 356.6,244.31 A02.L2 357.11,245.33 354.57,247.87 A03.K1 354.06,248.37 356.6,250.91 A02.J2 356.6,251.93 356.6,257.01 A02.F2 357.62,257.01 363.21,257.01 A02.F1 | A02.N2 357.62,238.21 363.21,238.21 A02.N1 363.71,239.23 363.71,241.26 366.76,244.31 369.3,244.31 AB01.AL2 | A02.R2 356.6,232.63 356.6,238.21 A02.N2 | 350.5,231.61 A03.R1 | A12.T1 230.62,226.53 233.67,226.53 235.19,228.05 238.24,228.05 239.76,226.53 242.3,226.53 A11.T1 243.32,226.53 246.37,226.53 247.89,228.05 250.94,228.05 252.46,226.53 255,226.53 A10.T1 256.02,226.53 259.06,226.53 260.59,228.05 263.64,228.05 265.16,226.53 267.7,226.53 A09.T1 268.72,225.51 277.35,225.51 A08.T2 278.37,225.51 283.96,225.51 A08.T1 284.47,226.53 288.53,226.53 290.05,228.05 292.09,228.05 293.61,226.53 296.66,226.53 A07.T1 297.17,225.51 299.71,222.97 A07.U1 300.21,222.47 305.8,222.47 A06.U2 306.82,222.97 309.36,225.51 A06.T1 309.36,226.53 309.36,231.61 | A05.N2 315.45,239.23 315.45,244.31 A05.L2 315.45,245.33 312.91,247.87 A06.K1 312.91,248.37 315.45,250.91 A05.J2 315.45,251.93 315.45,257.01
  Top 0.635: 315.45,257.01 A05.F2 | A06.N1 309.36,238.21 303.77,238.21 A06.N2 302.75,239.23 302.75,244.31 A06.L2 303.77,245.33 306.31,247.87 A06.K2 306.31,248.37 303.77,250.91 A06.J2 302.75,251.93 302.75,257.01 A06.F2 303.77,257.01 309.36,257.01 A06.F1 309.87,257.01 315.45,257.01 | 315.45,257.01 A05.F2 | 309.36,231.61 303.77,231.61 A06.R2 | 309.36,231.61 A06.R1 | A06.R1 309.87,231.61 315.45,231.61 A05.R2 316.47,231.61 322.06,231.61 A05.R1 | 309.36,231.61 A06.R1 | 325.11,254.47 322.56,257.01 A05.F1 | 325.11,254.47 A05.H1 325.11,254.47 | 325.11,254.47 322.56,251.93 A05.J1 322.56,250.91 325.11,248.37 A05.K1 325.11,247.87 322.56,245.33 A05.L1 322.56,244.31 325.11,241.77 | 325.11,241.77 A05.M1 | 325.11,241.77 322.56,239.23 A05.N1 322.56,238.21 325.11,235.67 A05.P1 325.11,235.17 322.56,232.63 A05.R1 | 325.11,241.77 A05.M1 | A05.U2 319.52,222.97 322.06,225.51 A05.T1 322.56,226.53 325.11,229.07 | 325.11,229.07 322.56,231.61 A05.R1 | 325.11,229.07 A05.S1 325.11,229.07 | A05.F2 316.47,257.01 322.06,257.01 A05.F1 | 331.2,241.26 325.61,241.26 A05.M1 | A16.C2 173.21,267.68 177.28,267.68 178.8,269.2 180.83,269.2 182.36,267.68 185.41,267.68 A15.C2 185.91,267.68 188.96,267.68 190.49,269.2 193.03,269.2 194.55,267.68 198.11,267.68 A14.C2 198.61,267.68 201.66,267.68 209.79,275.81 218.43,275.81 223.51,270.73 A12.B2 224.01,269.71 228.08,269.71 229.09,268.69 238.24,268.69 239.25,267.68 A11.C2 240.27,267.68 242.81,267.68 244.84,269.71 248.91,269.71 A10.B2 249.41,269.71 253.48,269.71 254.49,268.69 263.64,268.69 264.65,267.68 A09.C2 265.67,267.68 269.23,267.68 270.75,269.2 276.34,269.2 277.86,267.68 280.4,267.68 A08.C2 281.42,267.68 284.47,267.68 285.99,269.2 289.04,269.2 290.56,267.68 293.1,267.68 A07.C2 294.12,267.68 297.17,267.68 298.69,269.2 301.74,269.2 303.26,267.68 305.8,267.68 A06.C2 306.82,266.66 312.41,266.66 A06.C1
  Top 0.635: A04.C1 340.85,266.66 335.26,266.66 A04.C2 334.76,266.66 325.61,266.66 A05.C1 | A04.A1 340.85,273.27 340.85,267.68 A04.C1 | A04.C1 341.87,266.66 347.46,266.66 A03.C2 347.97,266.66 353.55,266.66 A03.C1 | A03.A1 353.55,273.27 353.55,267.68 A03.C1 | A03.C1 354.57,266.66 360.16,266.66 A02.C2 360.67,266.66 366.25,266.66 A02.C1 | A02.A1 366.25,273.27 366.25,267.68 A02.C1 | AB01.AC2 372.86,266.66 367.27,266.66 A02.C1 | A05.C1 325.11,266.66 322.56,264.12 A05.D1 322.56,263.61 325.11,261.07 A05.E1 325.11,260.57 322.56,258.03 A05.F1 | A06.C1 312.91,266.66 315.45,264.12 A05.D2 316.47,264.63 318.5,266.66 A05.C2 319.52,267.17 322.06,269.71 A05.B1 | A06.A1 312.41,273.27 312.41,267.68 A06.C1 | A05.A1 325.11,273.27 322.56,270.73 A05.B1 | A05.C1 325.11,267.68 322.56,270.22 A05.B1
I/O_BAC_03
  Bottom 0.254: D02.H1 367.27,51.78 367.27,54.32 384.03,71.08 384.03,82.77 384.54,83.27 384.54,234.15 371.84,246.85 371.84,249.39 371.33,249.9 368.79,249.9 367.27,251.42 367.27,253.96 A02.H1
I/O_BMB_03
  Bottom 0.254: 320.03,130.01 320.53,130.01 321.04,129.5 330.69,129.5 331.2,130.01 C04.D2 | 320.03,130.01 316.47,130.01 C05.D2 | 320.03,130.01 307.32,142.71 294.62,142.71 277.35,159.98 268.21,159.98 267.19,161 267.19,163.03 267.7,163.54 272.27,163.54 273.8,165.06 273.8,205.7 304.79,236.69 304.79,249.39 324.09,268.69 342.88,268.69 348.98,262.6 348.98,257.01 350.5,255.49 350.5,251.93 A03.J1
I/O_BMB_03\
  Bottom 0.254: D03.H1 354.57,51.78 354.57,54.32 384.03,83.78 384.03,233.64 364.73,252.95 355.59,252.95 354.57,253.96 A03.H1
I/O_BMB_04
  Bottom 0.254: C05.E2 319.52,126.96 323.58,126.96 326.63,123.91 329.17,123.91 332.22,126.96 334.76,126.96 C04.E2
I/O_BMB_06\
  Bottom 0.254: D03.D2 343.9,61.43 342.88,62.45 342.88,84.8 333.74,93.94 317.49,93.94 301.74,109.69 301.74,112.23 305.8,116.29 317.49,116.29 320.53,119.34 330.69,119.34 343.9,132.55 348.98,132.55 365.24,148.81 365.24,162.01 367.78,164.55 367.78,211.8 342.88,236.69 342.88,262.6 343.9,263.61 A03.D2
I/O_BMB_07
  Bottom 0.254: 346.44,52.79 346.44,46.19 347.46,45.17 D03.K2 | 346.44,52.79 346.44,54.83 318.5,82.77 295.64,82.77 295.13,83.27 290.05,83.27 285.48,87.85 285.48,90.89 285.99,91.4 292.09,91.4 301.23,100.55 301.23,112.74 307.83,119.34 310.37,119.34 311.39,118.33 315.45,118.33 C05.J2 | 346.44,52.79 363.21,69.56 363.21,85.81 C02.V1 | C04.J2 332.22,118.33 335.77,118.33 368.29,150.84 368.29,225.01 347.97,245.33 347.97,247.87 A03.K2
I/O_BMB_07\
  Bottom 0.254: D03.H2 347.97,50.76 347.97,47.21 358.12,37.05 361.68,37.05 385.56,60.92 385.56,239.23 365.75,259.04 355.59,259.04 352.03,255.49 352.03,249.9 350,249.9 347.97,251.93 347.97,253.96 A03.H2
I/O_BMB_08
  Bottom 0.254: C05.K2 319.52,115.28 323.58,115.28 324.6,116.29 346.44,116.29 357.11,126.96 360.16,126.96 C02.E2
I/O_BRK_RQ\
  Bottom 0.254: A05.K2 319.52,247.87 319.52,243.29 320.53,242.28 320.53,195.54 317.99,193 317.99,189.45 320.03,189.45 322.06,191.48 322.06,193.51 B05.D1
I/O_DATA_IN
  Bottom 0.254: B05.J2 315.45,181.32 315.45,183.86 313.93,185.38 296.66,185.38 295.64,186.4 295.64,188.43 296.15,188.94 313.42,188.94 317.49,193 317.49,229.58 317.99,230.09 317.99,240.75 318.5,241.26 A05.M2
IM_00\
  Bottom 0.254: B04.D1 338.31,193.51 342.88,193.51 343.39,193 350,193 350.5,193.51 B03.D1
IM_01\
  Bottom 0.254: 352.54,189.45 346.95,189.45 345.93,190.46 341.87,190.46 B04.E1 | 352.54,189.45 353.55,190.46 B03.E1 | 352.54,189.45 352.54,198.59 355.08,201.13 355.08,204.69 339.33,220.43 339.33,259.04 338.31,260.06 338.31,263.61 A04.D1
IM_02\
  Bottom 0.254: B04.K1 341.87,177.76 341.87,175.22 346.44,170.65 348.98,170.65 353.55,175.22 353.55,177.76 B03.K1
IM_03\
  Bottom 0.254: 346.95,170.14 349.49,170.14 355.08,175.73 355.08,179.29 354.57,179.79 353.55,179.79 351.01,177.25 351.01,175.73 B03.L1 | 346.95,170.14 345.93,170.14 341.36,174.71 338.31,174.71 B04.L1 | 346.95,170.14 355.08,162.01 355.08,157.95 354.57,157.44 349.49,157.44 339.84,147.79 339.84,139.66 340.85,138.65 342.38,138.65 356.09,152.36 356.09,204.69 339.84,220.94 339.84,249.39 340.85,250.41 340.85,253.96 A04.H1
IM_04\
  Bottom 0.254: B04.R1 338.31,163.03 342.88,163.03 343.39,163.54 350,163.54 350.5,163.03 B03.R1
IM_05\
  Bottom 0.254: B04.S1 341.87,159.47 345.43,159.47 346.44,160.49 352.54,160.49 353.55,159.47 B03.S1
IM_07\
  Bottom 0.254: B04.J2 332.22,180.81 333.23,179.79 342.38,179.79 343.9,181.32 B03.J2
IM_08\
  Bottom 0.254: B04.N2 332.22,169.13 336.28,169.13 337.3,170.14 342.88,170.14 343.9,169.13 B03.N2
IM_09\
  Bottom 0.254: B03.P2 347.46,165.06 342.88,165.06 341.36,163.54 326.12,163.54 313.93,151.35 297.17,151.35 290.56,157.95 290.56,159.47 285.48,164.55 285.48,170.14 282.43,173.19 282.43,186.91 276.34,193 276.34,195.03 304.79,223.48 304.79,225.01 311.39,231.61 311.39,243.8 331.2,263.61 A04.D2
IOP_1
  Bottom 0.254: D02.K2 360.67,45.17 363.21,45.17 385.05,67.02 385.05,238.72 367.78,255.99 353.55,255.99 352.54,254.98 352.54,253.45 357.62,248.37 360.16,248.37 A02.K2 | C05.P2 319.52,102.58 323.58,102.58 324.6,103.59 333.74,103.59 334.76,102.58 C04.P2
IOP_2
  Bottom 0.254: C05.R2 316.47,99.53 320.53,99.53 321.04,100.04 330.69,100.04 331.2,99.53 C04.R2 332.22,98.51 334.76,98.51 339.33,93.94 358.12,93.94 360.16,91.91 | 360.16,91.91 364.73,87.34 364.73,66 352.03,53.3 352.03,44.16 357.11,39.08 360.16,39.08 D02.M2 | 360.16,91.91 367.78,99.53 367.78,112.23 382,126.45 382,217.39 360.67,238.72 360.67,241.26 A02.M2
LDMF
  Bottom 0.254: 239.76,60.92 245.86,54.83 245.86,51.78 D11.H1 | 239.76,60.92 236.71,60.92 D11.D2 | 239.76,60.92 242.3,63.46 242.3,66.51 D11.B1
LPB_05
  Bottom 0.254: 198.61,22.31 200.65,24.35 226.05,24.35 235.7,14.69 258.56,14.69 262.11,11.14 281.42,11.14 285.48,15.2 285.48,17.23 284.97,17.74 279.38,17.74 278.37,16.73 D08.V2 | 198.61,22.31 185.91,9.61 139.18,9.61 118.35,30.44 114.28,30.44 58.91,85.81 58.91,94.96 22.34,131.53 22.34,249.39 31.99,259.04 31.99,265.14 33.51,266.66 36.05,266.66 A26.C2 | 198.61,22.31 211.31,9.61 293.61,9.61 304.79,20.79 304.79,61.94 295.13,71.59 293.1,71.59 281.42,83.27 281.42,88.86 C08.U2
LPB_05\
  Bottom 0.254: D10.U2 251.95,19.77 249.41,22.31 D10.T2 249.41,22.82 250.43,23.84 | 250.43,23.84 251.95,25.36 D10.S2 | 250.43,23.84 261.1,13.17 281.42,13.17 283.96,15.71 D08.V1
LPB_TO_DTB
  Bottom 0.254: C08.T2 278.37,92.93 278.37,95.47 284.47,101.56 287,101.56 C08.P1 | 279.89,123.91 280.91,123.91 283.45,121.37 | 279.89,123.91 278.37,123.91 C08.F2 | 283.45,121.37 283.96,120.87 283.96,118.33 C08.J1 | 279.89,123.91 279.89,113.75 280.4,113.25 280.4,108.67 C08.M2 | 283.45,121.37 285.48,123.41 285.48,127.98 287,129.5 287,133.57 C08.C1
MB_TO_DTB\
  Bottom 0.254: D12.S1 233.67,26.38 233.67,29.93 235.19,31.46 235.19,43.14 233.67,44.67 D12.K1 233.16,45.17 230.62,47.71 D12.J1 230.62,48.22 233.16,50.76 D12.H1 233.16,51.27 230.62,53.81 D12.F1
MC00
  Bottom 0.254: B13.E2 211.31,190.46 216.9,190.46 B13.E1
MC01
  Bottom 0.254: B13.J1 213.85,181.32 211.31,183.86 B13.H2
MC01\
  Bottom 0.254: C11.B1 242.3,137.63 242.3,141.19 235.19,148.3 235.19,151.85 245.86,162.52 245.86,165.06 B11.P1
MC02\
  Bottom 0.254: B13.M1 217.92,172.17 217.92,176.24 219.95,178.27 219.95,194.53 217.92,196.56 B13.C1
MF00\
  Bottom 0.254: B05.M1 325.61,172.17 325.61,175.73 328.15,178.27 328.15,189.95 331.71,193.51 B04.D2
MF01
  Bottom 0.254: D11.H2 239.25,51.78 235.19,51.78 231.12,55.84 223,55.84 219.44,52.29 219.44,49.24 182.87,12.66 141.21,12.66 110.22,43.65 102.09,43.65 59.42,86.32 59.42,95.47 25.89,128.99 25.89,247.87 34.53,256.5 34.53,263.11 42.66,271.23 42.66,273.27 A26.A1
MF01\
  Bottom 0.254: B05.N1 322.56,168.62 324.6,168.62 328.66,172.68 328.66,186.91 332.22,190.46 334.76,190.46 B04.E2
MK_BLK_MK
  Bottom 0.254: D10.B1 256.02,67.53 258.56,70.07 D10.A1
MK_BLK_START\
  Bottom 0.254: CD18.AF1 147.31,124.93 145.78,126.45 145.78,151.85 158.99,165.06 158.99,183.86 162.04,186.91 162.04,220.43 152.39,230.09 152.39,252.95 168.13,268.69 168.13,273.27 172.71,277.84 267.19,277.84 271.26,273.77 A09.A1
MK_END
  Bottom 0.254: CD18.AF2 140.7,124.93 140.7,128.99 140.19,129.5 140.19,157.44 151.88,169.13 151.88,258.03 172.2,278.35 280.4,278.35 285.99,272.76 285.99,269.2 287.51,267.68 A08.C1
MKT
  Bottom 0.254: B13.V2 208.27,149.82 208.27,152.36 219.44,163.54 224.52,163.54 226.55,161.51 226.55,159.47 B12.S2
MKT\
  Bottom 0.254: B13.T2 208.27,155.92 210.81,155.92 221.98,167.09 248.4,167.09 252.97,162.52 255,162.52 B10.R1 | C14.N1 202.17,105.63 202.17,108.67 215.38,121.88 215.38,148.3 214.87,148.81 B13.V1
N$2
  Bottom 0.254: C16.N2 170.17,105.63 172.71,108.17 C16.M2 173.21,108.67 175.75,108.67 177.28,110.2 177.28,112.74 175.75,114.26 173.21,114.26 C16.K2 172.71,114.77 170.17,112.23 C16.L2
N$4
  Bottom 0.254: D13.R2 208.27,28.41 210.81,25.87 D13.S2
N$6
  Bottom 0.254: D13.F2 208.27,54.83 212.33,54.83 219.95,62.45 228.59,62.45 229.6,61.43 D12.D1 230.62,60.92 233.16,63.46 D12.C1 233.16,63.97 230.62,66.51 D12.B1 230.62,67.53 233.16,70.07 D12.A1
N$7
  Bottom 0.254: A12.P1 233.16,235.67 230.62,238.21 A12.N1 229.6,239.23 228.59,240.25 228.59,248.37 229.6,249.39 229.6,250.91 A12.J1
N$12
  Bottom 0.254: D17.E2 156.96,57.87 154.42,60.41 D17.D2
N$13
  Bottom 0.254: B15.F1 189.47,187.92 189.47,190.97 203.19,204.69 203.19,225.51 206.23,228.56 206.23,238.21 198.61,245.83 198.61,247.87 A14.K2 198.11,248.37 195.57,250.91 A14.J2 195.57,251.42 198.11,253.96 A14.H2
N$14
  Bottom 0.254: A16.D2 170.17,263.61 172.71,261.07 A16.E2
N$15
  Bottom 0.254: C17.C1 163.05,133.57 163.05,131.03 154.93,122.9 152.89,122.9 152.89,138.65 165.09,150.84 165.09,252.44 169.66,257.01 A16.F2
N$16
  Bottom 0.254: C17.D2 154.42,131.03 154.42,135.09 165.59,146.27 165.59,250.41 180.33,265.14 187.95,265.14 188.45,264.63 A15.D1 189.47,264.63 191.5,266.66 A15.C1
N$17
  Bottom 0.254: B14.S2 198.61,159.47 198.61,163.03 201.15,165.57 201.15,168.11 B14.N1
N$18
  Bottom 0.254: B15.F2 182.87,187.92 185.41,187.92 197.09,199.61 197.09,234.15 198.11,235.17 A14.P2 198.11,235.67 195.57,238.21 A14.N2 195.57,238.72 198.11,241.26 A14.M2
N$19
  Bottom 0.254: A14.L2 195.06,245.33 195.06,248.88 194.04,249.9 194.04,252.44 197.6,255.99 203.19,255.99 204.2,254.98 A14.H1
N$20
  Bottom 0.254: A16.R2 170.17,231.61 172.71,229.07 A16.S2
N$21
  Bottom 0.254: A14.D2 195.57,263.61 198.11,261.07 A14.E2
N$23
  Bottom 0.254: A14.F2 195.57,258.03 199.63,258.03 200.65,259.04 204.2,259.04 223.51,239.74 225.54,239.74 234.17,231.1 237.73,231.1 239.25,232.63 239.25,235.17 A11.P2
N$25
  Bottom 0.254: A14.V2 195.57,219.93 195.57,223.99 196.58,225.01 196.58,230.59 195.57,231.61 A14.R2
N$26
  Bottom 0.254: A14.S2 198.61,228.56 204.2,228.56 A14.S1
N$27
  Bottom 0.254: D15.S2 185.41,26.38 185.41,29.93 182.87,32.47 182.87,35.01 D15.N2
N$29
  Bottom 0.254: B16.D2 170.17,193.51 172.71,190.97 B16.E2
N$31
  Bottom 0.254: C17.F2 154.42,124.93 154.42,128.49 162.04,136.11 162.04,141.19 166.1,145.25 166.1,249.9 179.82,263.61 182.36,263.61 A15.D2 182.87,263.61 185.41,261.07 A15.E2
N$32
  Bottom 0.254: C17.L1 160.51,112.23 160.51,114.77 168.64,122.9 168.64,133.06 191.5,155.92 191.5,158.46 B15.S1
N$33
  Bottom 0.254: B10.S1 259.06,158.46 263.64,158.46 264.65,157.44 265.67,157.44 266.69,158.46 266.69,163.54 273.29,170.14 273.29,212.81 280.4,219.93 280.4,222.47 A08.U2
N$37
  Bottom 0.254: B16.R2 170.17,161.51 172.71,158.97 B16.S2
N$39
  Bottom 0.254: C15.J1 188.45,118.33 188.45,123.91 C15.F1
N$42
  Bottom 0.254: C11.L1 243.32,112.23 245.86,114.77 C11.K1
N$43
  Bottom 0.254: A12.T2 223.51,226.53 223.51,230.09 222.49,231.1 222.49,237.2 223.51,238.21 A12.N2
N$45
  Bottom 0.254: A12.U2 226.55,222.97 226.55,228.56 A12.S2
N$46
  Bottom 0.254: A10.K1 259.06,248.37 262.62,248.37 265.16,250.91 267.7,250.91 A09.J1
N$49
  Bottom 0.254: B12.L1 230.62,174.21 234.68,174.21 235.19,173.7 243.83,173.7 244.33,174.21 244.33,175.22 240.78,178.78 240.78,189.95 240.27,190.46 B11.E2
N$52
  Bottom 0.254: C11.S1 245.86,95.97 245.86,98.01 239.76,104.1 235.19,104.1 235.19,113.25 240.78,118.83 240.78,128.49 240.27,128.99 234.68,128.99 233.67,127.98 C12.E1
N$53
  Bottom 0.254: C15.R1 188.45,99.53 185.91,99.53 184.39,101.05 184.39,103.09 185.91,104.61 188.45,104.61 C15.N1
N$54
  Bottom 0.254: C12.H1 233.67,121.37 236.21,123.91 C11.F2
N$55
  Bottom 0.254: B12.E1 233.67,190.97 236.21,193.51 B11.D2
N$56
  Bottom 0.254: B11.F2 236.71,187.92 236.71,189.95 240.27,193.51 242.3,193.51 B11.D1
N$59
  Bottom 0.254: C13.V1 214.87,86.83 221.98,86.83 226.05,90.89 240.27,90.89 240.78,90.39 240.78,88.35 239.25,86.83 236.71,86.83 C11.V2
N$62
  Bottom 0.254: B12.N2 223.51,168.62 223.51,172.68 222.49,173.7 222.49,179.79 223.51,180.81 B12.J2
N$63
  Bottom 0.254: B15.K1 192.52,177.76 196.07,177.76 205.22,168.62 207.76,168.62 B13.N2
N$64
  Bottom 0.254: B10.D1 256.02,194.02 258.56,196.56 B10.C1
N$65
  Bottom 0.254: C11.T2 236.71,92.93 239.25,95.47 C11.S2
N$66
  Bottom 0.254: B10.B1 256.02,200.62 258.56,203.16 B10.A1
N$68
  Bottom 0.254: D14.H1 204.71,51.78 204.71,54.32 198.61,60.41 196.07,60.41 D14.D2
N$69
  Bottom 0.254: D14.C1 204.71,64.48 204.71,70.07 D14.A1
N$72
  Bottom 0.254: B11.N1 243.32,168.62 245.35,168.62 247.38,170.65 247.38,173.19 241.79,178.78 241.79,182.33 243.32,183.86 245.86,183.86 B11.H1
N$77
  Bottom 0.254: B11.J1 243.32,181.32 246.87,181.32 252.46,186.91 255,186.91 B10.F1
N$79
  Bottom 0.254: C14.N2 195.57,104.61 200.14,104.61 200.65,104.1 207.25,104.1 207.76,104.61 C13.N2
N$81
  Bottom 0.254: C13.M2 211.31,108.67 213.85,108.67 221.98,116.8 221.98,120.36 229.6,127.98 229.6,130.01 C12.D1
N$84
  Bottom 0.254: A10.D1 256.02,264.63 258.56,267.17 A10.C1
N$85
  Bottom 0.254: A10.F1 255,258.03 255,262.09 254.49,262.6 254.49,269.2 255,269.71 A10.B1
N$88
  Bottom 0.254: D17.S2 156.96,26.38 154.42,28.92 D17.R2
N$91
  Bottom 0.254: B08.S1 287,159.47 282.43,159.47 280.91,161 269.23,161 268.72,161.51 B09.R1
N$93
  Bottom 0.254: D09.E1 271.76,57.87 282.43,68.54 284.97,68.54 287,66.51 287,64.48 D08.C1 287,63.97 284.47,61.43 D08.D1
N$94
  Bottom 0.254: D09.J2 262.11,48.73 265.67,48.73 270.75,53.81 277.35,53.81 D08.F2 277.86,54.83 280.4,57.37 D08.E2
N$95
  Bottom 0.254: D09.L1 268.72,42.13 268.72,45.68 269.73,46.7 282.94,46.7 283.96,47.71 D08.J1 284.47,47.71 287,45.17 D08.K1
N$96
  Bottom 0.254: D09.S1 271.76,26.38 279.38,26.38 281.42,28.41 283.96,28.41 D08.R1 284.47,29.43 287,31.97 D08.P1
N$99
  Bottom 0.254: 267.7,18.25 271.76,22.31 277.35,22.31 D08.T2 | 267.7,18.25 266.18,16.73 262.11,16.73 D09.V2 | 267.7,18.25 272.78,18.25 273.8,19.27 280.4,19.27 D08.U2
N$100
  Bottom 0.254: D09.P2 265.67,32.47 265.67,37.05 270.24,41.62 270.24,46.19 272.78,46.19 276.34,42.63 276.34,37.05 277.35,36.03 D08.N2 278.37,36.03 280.4,38.06 D08.M2
N$101
  Bottom 0.254: 288.53,43.65 283.45,43.65 281.93,42.13 278.37,42.13 D08.L2 | 288.53,43.65 288.53,47.71 282.43,53.81 282.43,58.89 280.91,60.41 278.37,60.41 D08.D2 | 288.53,43.65 278.88,34 277.35,34 270.24,26.89 270.24,24.85 270.75,24.35 272.27,24.35 273.29,25.36 280.4,25.36 D08.S2
N$103
  Bottom 0.254: D08.N1 284.47,36.03 284.47,38.57 289.04,43.14 289.04,49.24 287.51,50.76 D08.H1 287,51.78 287,53.81 282.94,57.87 282.94,61.94 283.96,62.95 283.96,66.51 D08.B1
N$105
  Bottom 0.254: A11.A1 246.37,273.27 249.92,273.27 251.45,271.74 256.53,271.74 267.19,261.07 271.26,261.07 A09.E1
N$106
  Bottom 0.254: A11.B1 243.32,270.73 243.32,273.27 244.84,274.79 255,274.79 267.7,262.09 272.78,262.09 272.78,259.55 268.21,254.98 265.67,254.98 A09.H2
N$118
  Bottom 0.254: D12.L2 224.01,42.13 226.55,44.67 D12.K2
N$123
  Bottom 0.254: 135.11,260.57 138.16,263.61 140.7,263.61 A18.D2 | 135.11,260.57 132.57,258.03 129.02,258.03 AB19.AF2 | 135.11,260.57 140.7,254.98 140.7,251.93 A18.J2
N$126
  Bottom 0.254: 143.24,247.87 144.26,247.87 A18.K2 | 143.24,247.87 142.23,247.87 136.13,253.96 132.07,253.96 AB19.AH2 | 143.24,247.87 143.24,255.49 144.26,256.5 144.26,260.57 A18.E2
N$127
  Bottom 0.254: B18.J2 140.7,181.83 140.7,185.89 140.19,186.4 140.19,193 140.7,193.51 B18.D2 141.72,194.53 142.73,195.54 142.73,227.04 131.56,238.21 129.02,238.21 AB19.AN2
N$130
  Bottom 0.254: 145.78,189.45 145.78,183.35 144.77,182.33 144.77,178.78 B18.K2 | 145.78,189.45 144.77,190.46 B18.E2 | 145.78,189.45 145.78,225.01 131.05,239.74 127.49,239.74 127.49,237.2 129.02,235.67 131.56,235.67 AB19.AP2
N$131
  Bottom 0.254: 114.79,256.5 115.3,255.99 115.3,251.93 A20.J2 | 114.79,256.5 114.79,263.11 115.3,263.61 A20.D2 | 114.79,256.5 114.79,237.2 128,223.99 128,219.93 AB19.AV2
N$133
  Bottom 0.254: A20.E2 119.36,260.57 120.38,259.55 120.38,253.45 119.36,252.44 119.36,248.37 A20.K2 119.36,247.87 119.36,244.31 130.03,233.64 130.03,199.61 129.02,198.59 129.02,194.53 AB19.BD2
N$134
  Bottom 0.254: B20.J2 115.3,181.83 115.3,185.89 114.28,186.91 114.28,192.49 115.3,193.51 B20.D2 116.32,194.53 117.33,195.54 117.33,201.64 114.79,204.18 114.79,233.64 116.83,233.64 123.43,227.04 123.43,196.56 131.56,188.43 131.56,184.87 AB19.BH2
N$135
